VERSION 5.7 ;
DIVIDERCHAR "/" ;
BUSBITCHARS "[]" ;

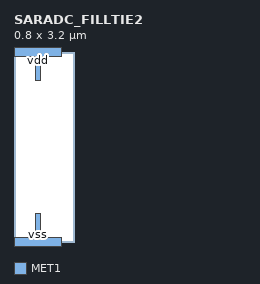
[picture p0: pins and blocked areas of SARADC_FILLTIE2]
MACRO SARADC_FILLTIE2
  CLASS BLOCK ;
  FOREIGN SARADC_FILLTIE2 ;
  ORIGIN 0.000 0.000 ;
  SIZE 0.800 BY 3.200 ;
  SYMMETRY X Y R90 ;
  PIN vdd
    DIRECTION INOUT ;
    USE POWER ;
    PORT
      LAYER MET1 ;
        RECT 0.355 2.715 0.445 3.120 ;
        RECT 0.000 3.120 0.800 3.280 ;
    END
  END vdd
  PIN vss
    DIRECTION INOUT ;
    USE GROUND ;
    PORT
      LAYER MET1 ;
        RECT 0.000 -0.080 0.800 0.080 ;
        RECT 0.355 0.080 0.445 0.485 ;
    END
  END vss
END SARADC_FILLTIE2

END LIBRARY
